VERSION 5.7 ;
  NOWIREEXTENSIONATPIN ON ;
  DIVIDERCHAR "/" ;
  BUSBITCHARS "[]" ;
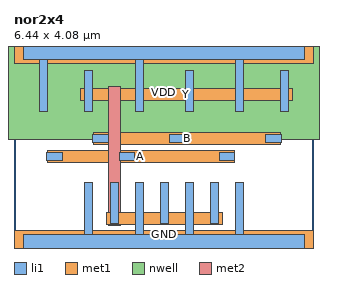
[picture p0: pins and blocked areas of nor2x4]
MACRO nor2x4
  CLASS BLOCK ;
  FOREIGN nor2x4 ;
  ORIGIN 0.000 0.000 ;
  SIZE 6.440 BY 4.080 ;
  PIN A
    ANTENNAGATEAREA 1.495200 ;
    PORT
      LAYER li1 ;
        RECT 0.705 1.745 1.035 1.915 ;
        RECT 2.255 1.745 2.585 1.915 ;
        RECT 4.415 1.745 4.745 1.915 ;
      LAYER met1 ;
        RECT 0.710 1.700 4.740 1.960 ;
    END
  END A
  PIN B
    ANTENNAGATEAREA 1.495200 ;
    PORT
      LAYER li1 ;
        RECT 1.695 2.145 2.025 2.315 ;
        RECT 3.335 2.145 3.665 2.315 ;
        RECT 5.405 2.145 5.735 2.315 ;
      LAYER met1 ;
        RECT 1.700 2.100 5.730 2.360 ;
    END
  END B
  PIN VDD
    ANTENNADIFFAREA 2.548600 ;
    PORT
      LAYER nwell ;
        RECT -0.230 2.200 6.670 4.410 ;
      LAYER li1 ;
        RECT 0.210 3.915 6.230 4.245 ;
        RECT 0.545 2.800 0.715 3.915 ;
        RECT 2.605 2.800 2.775 3.915 ;
        RECT 4.765 2.800 4.935 3.915 ;
      LAYER met1 ;
        RECT 0.000 3.840 6.440 4.320 ;
    END
  END VDD
  PIN GND
    ANTENNADIFFAREA 2.712400 ;
    PORT
      LAYER li1 ;
        RECT 1.505 0.165 1.675 1.280 ;
        RECT 2.605 0.165 2.775 1.280 ;
        RECT 3.685 0.165 3.855 1.280 ;
        RECT 4.765 0.165 4.935 1.280 ;
        RECT 0.210 -0.165 6.230 0.165 ;
      LAYER met1 ;
        RECT 0.000 -0.240 6.440 0.240 ;
    END
  END GND
  PIN Y
    ANTENNADIFFAREA 1.507800 ;
    PORT
      LAYER li1 ;
        RECT 1.505 2.800 1.675 3.680 ;
        RECT 3.685 2.800 3.855 3.680 ;
        RECT 5.725 2.800 5.895 3.680 ;
        RECT 2.065 0.400 2.235 1.280 ;
        RECT 3.145 0.400 3.315 1.280 ;
        RECT 4.225 0.400 4.395 1.280 ;
      LAYER met1 ;
        RECT 1.430 3.040 5.970 3.300 ;
        RECT 1.990 0.380 4.470 0.640 ;
      LAYER met2 ;
        RECT 2.020 0.350 2.280 3.330 ;
    END
  END Y
  OBS
      LAYER li1 ;
        RECT 1.025 2.800 1.195 3.680 ;
        RECT 2.065 2.800 2.235 3.680 ;
        RECT 3.145 2.800 3.315 3.680 ;
        RECT 4.225 2.800 4.395 3.680 ;
        RECT 5.245 2.800 5.415 3.680 ;
      LAYER met1 ;
        RECT 0.950 3.440 5.490 3.700 ;
        RECT 0.950 3.040 1.270 3.300 ;
      LAYER met2 ;
        RECT 0.980 3.010 1.240 3.730 ;
  END
END nor2x4
END LIBRARY

